VERSION 5.7 ;
  NOWIREEXTENSIONATPIN ON ;
  DIVIDERCHAR "/" ;
  BUSBITCHARS "[]" ;
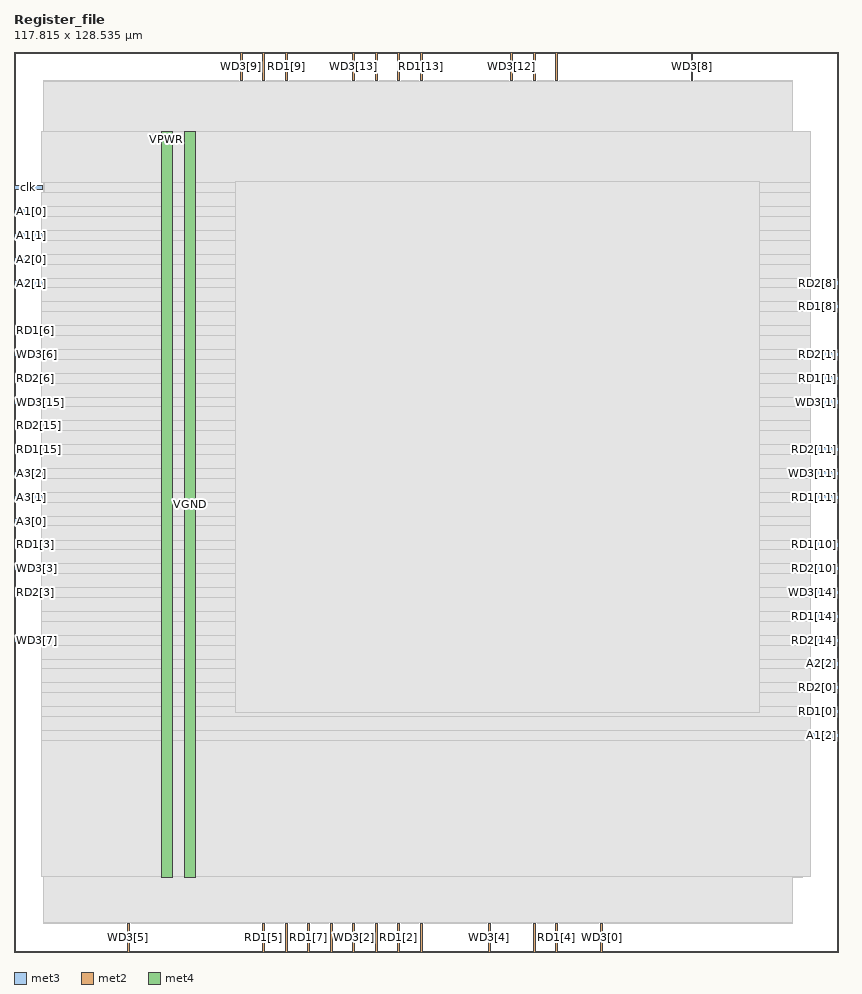
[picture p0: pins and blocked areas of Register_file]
MACRO Register_file
  CLASS BLOCK ;
  FOREIGN Register_file ;
  ORIGIN 0.000 0.000 ;
  SIZE 117.815 BY 128.535 ;
  PIN A1[0]
    DIRECTION INPUT ;
    USE SIGNAL ;
    ANTENNAGATEAREA 0.213000 ;
    PORT
      LAYER met3 ;
        RECT 0.000 105.440 4.000 106.040 ;
    END
  END A1[0]
  PIN A1[1]
    DIRECTION INPUT ;
    USE SIGNAL ;
    ANTENNAGATEAREA 0.196500 ;
    PORT
      LAYER met3 ;
        RECT 0.000 102.040 4.000 102.640 ;
    END
  END A1[1]
  PIN A1[2]
    DIRECTION INPUT ;
    USE SIGNAL ;
    ANTENNAGATEAREA 0.196500 ;
    PORT
      LAYER met3 ;
        RECT 113.815 30.640 117.815 31.240 ;
    END
  END A1[2]
  PIN A2[0]
    DIRECTION INPUT ;
    USE SIGNAL ;
    ANTENNAGATEAREA 0.126000 ;
    PORT
      LAYER met3 ;
        RECT 0.000 98.640 4.000 99.240 ;
    END
  END A2[0]
  PIN A2[1]
    DIRECTION INPUT ;
    USE SIGNAL ;
    ANTENNAGATEAREA 0.196500 ;
    PORT
      LAYER met3 ;
        RECT 0.000 95.240 4.000 95.840 ;
    END
  END A2[1]
  PIN A2[2]
    DIRECTION INPUT ;
    USE SIGNAL ;
    ANTENNAGATEAREA 0.196500 ;
    PORT
      LAYER met3 ;
        RECT 113.815 40.840 117.815 41.440 ;
    END
  END A2[2]
  PIN A3[0]
    DIRECTION INPUT ;
    USE SIGNAL ;
    ANTENNAGATEAREA 0.196500 ;
    PORT
      LAYER met3 ;
        RECT 0.000 61.240 4.000 61.840 ;
    END
  END A3[0]
  PIN A3[1]
    DIRECTION INPUT ;
    USE SIGNAL ;
    ANTENNAGATEAREA 0.196500 ;
    PORT
      LAYER met3 ;
        RECT 0.000 64.640 4.000 65.240 ;
    END
  END A3[1]
  PIN A3[2]
    DIRECTION INPUT ;
    USE SIGNAL ;
    ANTENNAGATEAREA 0.196500 ;
    PORT
      LAYER met3 ;
        RECT 0.000 68.040 4.000 68.640 ;
    END
  END A3[2]
  PIN RD1[0]
    DIRECTION OUTPUT ;
    USE SIGNAL ;
    ANTENNADIFFAREA 0.445500 ;
    PORT
      LAYER met3 ;
        RECT 113.815 34.040 117.815 34.640 ;
    END
  END RD1[0]
  PIN RD1[10]
    DIRECTION OUTPUT ;
    USE SIGNAL ;
    ANTENNADIFFAREA 0.445500 ;
    PORT
      LAYER met3 ;
        RECT 113.815 57.840 117.815 58.440 ;
    END
  END RD1[10]
  PIN RD1[11]
    DIRECTION OUTPUT ;
    USE SIGNAL ;
    ANTENNADIFFAREA 0.445500 ;
    PORT
      LAYER met3 ;
        RECT 113.815 64.640 117.815 65.240 ;
    END
  END RD1[11]
  PIN RD1[12]
    DIRECTION OUTPUT ;
    USE SIGNAL ;
    ANTENNADIFFAREA 0.445500 ;
    PORT
      LAYER met2 ;
        RECT 77.370 124.535 77.650 128.535 ;
    END
  END RD1[12]
  PIN RD1[13]
    DIRECTION OUTPUT ;
    USE SIGNAL ;
    ANTENNADIFFAREA 0.445500 ;
    PORT
      LAYER met2 ;
        RECT 58.050 124.535 58.330 128.535 ;
    END
  END RD1[13]
  PIN RD1[14]
    DIRECTION OUTPUT ;
    USE SIGNAL ;
    ANTENNADIFFAREA 0.445500 ;
    PORT
      LAYER met3 ;
        RECT 113.815 47.640 117.815 48.240 ;
    END
  END RD1[14]
  PIN RD1[15]
    DIRECTION OUTPUT ;
    USE SIGNAL ;
    ANTENNADIFFAREA 0.445500 ;
    PORT
      LAYER met3 ;
        RECT 0.000 71.440 4.000 72.040 ;
    END
  END RD1[15]
  PIN RD1[1]
    DIRECTION OUTPUT ;
    USE SIGNAL ;
    ANTENNADIFFAREA 0.445500 ;
    PORT
      LAYER met3 ;
        RECT 113.815 81.640 117.815 82.240 ;
    END
  END RD1[1]
  PIN RD1[2]
    DIRECTION OUTPUT ;
    USE SIGNAL ;
    ANTENNADIFFAREA 0.445500 ;
    PORT
      LAYER met2 ;
        RECT 54.830 0.000 55.110 4.000 ;
    END
  END RD1[2]
  PIN RD1[3]
    DIRECTION OUTPUT ;
    USE SIGNAL ;
    ANTENNADIFFAREA 0.445500 ;
    PORT
      LAYER met3 ;
        RECT 0.000 57.840 4.000 58.440 ;
    END
  END RD1[3]
  PIN RD1[4]
    DIRECTION OUTPUT ;
    USE SIGNAL ;
    ANTENNADIFFAREA 0.445500 ;
    PORT
      LAYER met2 ;
        RECT 77.370 0.000 77.650 4.000 ;
    END
  END RD1[4]
  PIN RD1[5]
    DIRECTION OUTPUT ;
    USE SIGNAL ;
    ANTENNADIFFAREA 0.445500 ;
    PORT
      LAYER met2 ;
        RECT 35.510 0.000 35.790 4.000 ;
    END
  END RD1[5]
  PIN RD1[6]
    DIRECTION OUTPUT ;
    USE SIGNAL ;
    ANTENNADIFFAREA 0.445500 ;
    PORT
      LAYER met3 ;
        RECT 0.000 88.440 4.000 89.040 ;
    END
  END RD1[6]
  PIN RD1[7]
    DIRECTION OUTPUT ;
    USE SIGNAL ;
    ANTENNADIFFAREA 0.445500 ;
    PORT
      LAYER met2 ;
        RECT 41.950 0.000 42.230 4.000 ;
    END
  END RD1[7]
  PIN RD1[8]
    DIRECTION OUTPUT ;
    USE SIGNAL ;
    ANTENNADIFFAREA 0.445500 ;
    PORT
      LAYER met3 ;
        RECT 113.815 91.840 117.815 92.440 ;
    END
  END RD1[8]
  PIN RD1[9]
    DIRECTION OUTPUT ;
    USE SIGNAL ;
    ANTENNADIFFAREA 0.445500 ;
    PORT
      LAYER met2 ;
        RECT 38.730 124.535 39.010 128.535 ;
    END
  END RD1[9]
  PIN RD2[0]
    DIRECTION OUTPUT ;
    USE SIGNAL ;
    ANTENNADIFFAREA 0.445500 ;
    PORT
      LAYER met3 ;
        RECT 113.815 37.440 117.815 38.040 ;
    END
  END RD2[0]
  PIN RD2[10]
    DIRECTION OUTPUT ;
    USE SIGNAL ;
    ANTENNADIFFAREA 0.445500 ;
    PORT
      LAYER met3 ;
        RECT 113.815 54.440 117.815 55.040 ;
    END
  END RD2[10]
  PIN RD2[11]
    DIRECTION OUTPUT ;
    USE SIGNAL ;
    ANTENNADIFFAREA 0.445500 ;
    PORT
      LAYER met3 ;
        RECT 113.815 71.440 117.815 72.040 ;
    END
  END RD2[11]
  PIN RD2[12]
    DIRECTION OUTPUT ;
    USE SIGNAL ;
    ANTENNADIFFAREA 0.445500 ;
    PORT
      LAYER met2 ;
        RECT 74.150 124.535 74.430 128.535 ;
    END
  END RD2[12]
  PIN RD2[13]
    DIRECTION OUTPUT ;
    USE SIGNAL ;
    ANTENNADIFFAREA 0.445500 ;
    PORT
      LAYER met2 ;
        RECT 51.610 124.535 51.890 128.535 ;
    END
  END RD2[13]
  PIN RD2[14]
    DIRECTION OUTPUT ;
    USE SIGNAL ;
    ANTENNADIFFAREA 0.445500 ;
    PORT
      LAYER met3 ;
        RECT 113.815 44.240 117.815 44.840 ;
    END
  END RD2[14]
  PIN RD2[15]
    DIRECTION OUTPUT ;
    USE SIGNAL ;
    ANTENNADIFFAREA 0.445500 ;
    PORT
      LAYER met3 ;
        RECT 0.000 74.840 4.000 75.440 ;
    END
  END RD2[15]
  PIN RD2[1]
    DIRECTION OUTPUT ;
    USE SIGNAL ;
    ANTENNADIFFAREA 0.445500 ;
    PORT
      LAYER met3 ;
        RECT 113.815 85.040 117.815 85.640 ;
    END
  END RD2[1]
  PIN RD2[2]
    DIRECTION OUTPUT ;
    USE SIGNAL ;
    ANTENNADIFFAREA 0.445500 ;
    PORT
      LAYER met2 ;
        RECT 51.610 0.000 51.890 4.000 ;
    END
  END RD2[2]
  PIN RD2[3]
    DIRECTION OUTPUT ;
    USE SIGNAL ;
    ANTENNADIFFAREA 0.445500 ;
    PORT
      LAYER met3 ;
        RECT 0.000 51.040 4.000 51.640 ;
    END
  END RD2[3]
  PIN RD2[4]
    DIRECTION OUTPUT ;
    USE SIGNAL ;
    ANTENNADIFFAREA 0.445500 ;
    PORT
      LAYER met2 ;
        RECT 74.150 0.000 74.430 4.000 ;
    END
  END RD2[4]
  PIN RD2[5]
    DIRECTION OUTPUT ;
    USE SIGNAL ;
    ANTENNADIFFAREA 0.445500 ;
    PORT
      LAYER met2 ;
        RECT 38.730 0.000 39.010 4.000 ;
    END
  END RD2[5]
  PIN RD2[6]
    DIRECTION OUTPUT ;
    USE SIGNAL ;
    ANTENNADIFFAREA 0.445500 ;
    PORT
      LAYER met3 ;
        RECT 0.000 81.640 4.000 82.240 ;
    END
  END RD2[6]
  PIN RD2[7]
    DIRECTION OUTPUT ;
    USE SIGNAL ;
    ANTENNADIFFAREA 0.445500 ;
    PORT
      LAYER met2 ;
        RECT 45.170 0.000 45.450 4.000 ;
    END
  END RD2[7]
  PIN RD2[8]
    DIRECTION OUTPUT ;
    USE SIGNAL ;
    ANTENNADIFFAREA 0.445500 ;
    PORT
      LAYER met3 ;
        RECT 113.815 95.240 117.815 95.840 ;
    END
  END RD2[8]
  PIN RD2[9]
    DIRECTION OUTPUT ;
    USE SIGNAL ;
    ANTENNADIFFAREA 0.445500 ;
    PORT
      LAYER met2 ;
        RECT 35.510 124.535 35.790 128.535 ;
    END
  END RD2[9]
  PIN RegWrite
    DIRECTION INPUT ;
    USE SIGNAL ;
    ANTENNAGATEAREA 0.213000 ;
    PORT
      LAYER met2 ;
        RECT 54.830 124.535 55.110 128.535 ;
    END
  END RegWrite
  PIN VGND
    DIRECTION INOUT ;
    USE GROUND ;
    PORT
      LAYER met4 ;
        RECT 24.340 10.640 25.940 117.200 ;
    END
  END VGND
  PIN VPWR
    DIRECTION INOUT ;
    USE POWER ;
    PORT
      LAYER met4 ;
        RECT 21.040 10.640 22.640 117.200 ;
    END
  END VPWR
  PIN WD3[0]
    DIRECTION INPUT ;
    USE SIGNAL ;
    ANTENNAGATEAREA 0.213000 ;
    PORT
      LAYER met2 ;
        RECT 83.810 0.000 84.090 4.000 ;
    END
  END WD3[0]
  PIN WD3[10]
    DIRECTION INPUT ;
    USE SIGNAL ;
    ANTENNAGATEAREA 0.213000 ;
    PORT
      LAYER met2 ;
        RECT 58.050 0.000 58.330 4.000 ;
    END
  END WD3[10]
  PIN WD3[11]
    DIRECTION INPUT ;
    USE SIGNAL ;
    ANTENNAGATEAREA 0.126000 ;
    PORT
      LAYER met3 ;
        RECT 113.815 68.040 117.815 68.640 ;
    END
  END WD3[11]
  PIN WD3[12]
    DIRECTION INPUT ;
    USE SIGNAL ;
    ANTENNAGATEAREA 0.213000 ;
    PORT
      LAYER met2 ;
        RECT 70.930 124.535 71.210 128.535 ;
    END
  END WD3[12]
  PIN WD3[13]
    DIRECTION INPUT ;
    USE SIGNAL ;
    ANTENNAGATEAREA 0.126000 ;
    PORT
      LAYER met2 ;
        RECT 48.390 124.535 48.670 128.535 ;
    END
  END WD3[13]
  PIN WD3[14]
    DIRECTION INPUT ;
    USE SIGNAL ;
    ANTENNAGATEAREA 0.126000 ;
    PORT
      LAYER met3 ;
        RECT 113.815 51.040 117.815 51.640 ;
    END
  END WD3[14]
  PIN WD3[15]
    DIRECTION INPUT ;
    USE SIGNAL ;
    ANTENNAGATEAREA 0.213000 ;
    PORT
      LAYER met3 ;
        RECT 0.000 78.240 4.000 78.840 ;
    END
  END WD3[15]
  PIN WD3[1]
    DIRECTION INPUT ;
    USE SIGNAL ;
    ANTENNAGATEAREA 0.126000 ;
    PORT
      LAYER met3 ;
        RECT 113.815 78.240 117.815 78.840 ;
    END
  END WD3[1]
  PIN WD3[2]
    DIRECTION INPUT ;
    USE SIGNAL ;
    ANTENNAGATEAREA 0.126000 ;
    PORT
      LAYER met2 ;
        RECT 48.390 0.000 48.670 4.000 ;
    END
  END WD3[2]
  PIN WD3[3]
    DIRECTION INPUT ;
    USE SIGNAL ;
    ANTENNAGATEAREA 0.126000 ;
    PORT
      LAYER met3 ;
        RECT 0.000 54.440 4.000 55.040 ;
    END
  END WD3[3]
  PIN WD3[4]
    DIRECTION INPUT ;
    USE SIGNAL ;
    ANTENNAGATEAREA 0.126000 ;
    PORT
      LAYER met2 ;
        RECT 67.710 0.000 67.990 4.000 ;
    END
  END WD3[4]
  PIN WD3[5]
    DIRECTION INPUT ;
    USE SIGNAL ;
    ANTENNAGATEAREA 0.213000 ;
    PORT
      LAYER met2 ;
        RECT 16.190 0.000 16.470 4.000 ;
    END
  END WD3[5]
  PIN WD3[6]
    DIRECTION INPUT ;
    USE SIGNAL ;
    ANTENNAGATEAREA 0.126000 ;
    PORT
      LAYER met3 ;
        RECT 0.000 85.040 4.000 85.640 ;
    END
  END WD3[6]
  PIN WD3[7]
    DIRECTION INPUT ;
    USE SIGNAL ;
    ANTENNAGATEAREA 0.213000 ;
    PORT
      LAYER met3 ;
        RECT 0.000 44.240 4.000 44.840 ;
    END
  END WD3[7]
  PIN WD3[8]
    DIRECTION INPUT ;
    USE SIGNAL ;
    ANTENNAGATEAREA 0.213000 ;
    PORT
      LAYER met2 ;
        RECT 96.690 124.535 96.970 128.535 ;
    END
  END WD3[8]
  PIN WD3[9]
    DIRECTION INPUT ;
    USE SIGNAL ;
    ANTENNAGATEAREA 0.126000 ;
    PORT
      LAYER met2 ;
        RECT 32.290 124.535 32.570 128.535 ;
    END
  END WD3[9]
  PIN clk
    DIRECTION INPUT ;
    USE SIGNAL ;
    ANTENNAGATEAREA 0.852000 ;
    PORT
      LAYER met3 ;
        RECT 0.000 108.840 4.000 109.440 ;
    END
  END clk
  OBS
      LAYER nwell ;
        RECT 5.330 10.795 112.430 117.150 ;
      LAYER li1 ;
        RECT 5.520 10.795 112.240 117.045 ;
      LAYER met1 ;
        RECT 4.210 10.640 112.540 117.200 ;
      LAYER met2 ;
        RECT 4.230 124.255 32.010 124.535 ;
        RECT 32.850 124.255 35.230 124.535 ;
        RECT 36.070 124.255 38.450 124.535 ;
        RECT 39.290 124.255 48.110 124.535 ;
        RECT 48.950 124.255 51.330 124.535 ;
        RECT 52.170 124.255 54.550 124.535 ;
        RECT 55.390 124.255 57.770 124.535 ;
        RECT 58.610 124.255 70.650 124.535 ;
        RECT 71.490 124.255 73.870 124.535 ;
        RECT 74.710 124.255 77.090 124.535 ;
        RECT 77.930 124.255 96.410 124.535 ;
        RECT 97.250 124.255 111.220 124.535 ;
        RECT 4.230 4.280 111.220 124.255 ;
        RECT 4.230 4.000 15.910 4.280 ;
        RECT 16.750 4.000 35.230 4.280 ;
        RECT 36.070 4.000 38.450 4.280 ;
        RECT 39.290 4.000 41.670 4.280 ;
        RECT 42.510 4.000 44.890 4.280 ;
        RECT 45.730 4.000 48.110 4.280 ;
        RECT 48.950 4.000 51.330 4.280 ;
        RECT 52.170 4.000 54.550 4.280 ;
        RECT 55.390 4.000 57.770 4.280 ;
        RECT 58.610 4.000 67.430 4.280 ;
        RECT 68.270 4.000 73.870 4.280 ;
        RECT 74.710 4.000 77.090 4.280 ;
        RECT 77.930 4.000 83.530 4.280 ;
        RECT 84.370 4.000 111.220 4.280 ;
      LAYER met3 ;
        RECT 3.990 109.840 113.815 117.125 ;
        RECT 4.400 108.440 113.815 109.840 ;
        RECT 3.990 106.440 113.815 108.440 ;
        RECT 4.400 105.040 113.815 106.440 ;
        RECT 3.990 103.040 113.815 105.040 ;
        RECT 4.400 101.640 113.815 103.040 ;
        RECT 3.990 99.640 113.815 101.640 ;
        RECT 4.400 98.240 113.815 99.640 ;
        RECT 3.990 96.240 113.815 98.240 ;
        RECT 4.400 94.840 113.415 96.240 ;
        RECT 3.990 92.840 113.815 94.840 ;
        RECT 3.990 91.440 113.415 92.840 ;
        RECT 3.990 89.440 113.815 91.440 ;
        RECT 4.400 88.040 113.815 89.440 ;
        RECT 3.990 86.040 113.815 88.040 ;
        RECT 4.400 84.640 113.415 86.040 ;
        RECT 3.990 82.640 113.815 84.640 ;
        RECT 4.400 81.240 113.415 82.640 ;
        RECT 3.990 79.240 113.815 81.240 ;
        RECT 4.400 77.840 113.415 79.240 ;
        RECT 3.990 75.840 113.815 77.840 ;
        RECT 4.400 74.440 113.815 75.840 ;
        RECT 3.990 72.440 113.815 74.440 ;
        RECT 4.400 71.040 113.415 72.440 ;
        RECT 3.990 69.040 113.815 71.040 ;
        RECT 4.400 67.640 113.415 69.040 ;
        RECT 3.990 65.640 113.815 67.640 ;
        RECT 4.400 64.240 113.415 65.640 ;
        RECT 3.990 62.240 113.815 64.240 ;
        RECT 4.400 60.840 113.815 62.240 ;
        RECT 3.990 58.840 113.815 60.840 ;
        RECT 4.400 57.440 113.415 58.840 ;
        RECT 3.990 55.440 113.815 57.440 ;
        RECT 4.400 54.040 113.415 55.440 ;
        RECT 3.990 52.040 113.815 54.040 ;
        RECT 4.400 50.640 113.415 52.040 ;
        RECT 3.990 48.640 113.815 50.640 ;
        RECT 3.990 47.240 113.415 48.640 ;
        RECT 3.990 45.240 113.815 47.240 ;
        RECT 4.400 43.840 113.415 45.240 ;
        RECT 3.990 41.840 113.815 43.840 ;
        RECT 3.990 40.440 113.415 41.840 ;
        RECT 3.990 38.440 113.815 40.440 ;
        RECT 3.990 37.040 113.415 38.440 ;
        RECT 3.990 35.040 113.815 37.040 ;
        RECT 3.990 33.640 113.415 35.040 ;
        RECT 3.990 31.640 113.815 33.640 ;
        RECT 3.990 30.240 113.415 31.640 ;
        RECT 3.990 10.715 113.815 30.240 ;
      LAYER met4 ;
        RECT 31.575 34.175 106.425 109.985 ;
  END
END Register_file
END LIBRARY

